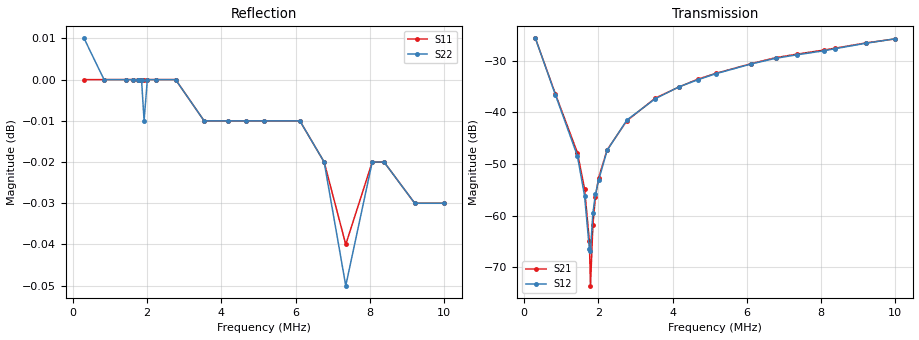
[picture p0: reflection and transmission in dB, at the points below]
!s-Parameter Generated by FASTRON Sdn. Bhd.
!FASTRON P/N : 1812AFTC-102X
!Keysight Technologies: E5071C_MY46733604_B.14.02
!Date: Wed Mar 18 13:59:20 2026
!Version  :Rev00  Wed Mar 18 13:59:20 2026
!Data & Calibration Information:
!Freq  S11:SOLT2(ON)  S21:SOLT2(ON)  S12:SOLT2(ON)  S22:SOLT2(ON)
!PortZ  Port1:50+j0  Port2:50+j0
!When reading reference impedance value at option line is always used.
! Remarks : This data is being provided solely for informational purposes.
# Hz S dB R 50
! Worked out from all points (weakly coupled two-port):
!   1601 points, 300 kHz to 10 MHz, reference 50 ohm
!   highest |S21| = -25.67 dB at 300 kHz (marker M1); lowest = -73.6 dB at 1.784 MHz (marker M2)
!   lowest |S11| = 0.0 dB at 7.353 MHz (marker M3), VSWR 465.81, Z = 0.15 - j31.6 ohm
!   |S11| at or under -10 dB: nowhere
!   |S22| runs from -0.1 to 0.0 dB; largest |S21 - S12| = 0.00091
!   S11 on the Smith chart (normalised r, x): 300 kHz: -0.01, +8.99; 2.232 MHz: 0.00, +1.31; 4.173 MHz: 0.00, +0.37; 6.115 MHz: 0.00, -0.21; 8.066 MHz: 0.00, -0.97; 10 MHz: 0.03, -4.09
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300000  0.00 12.7  -25.67 -85.6  -25.67 -85.4  0.01 -8.4
838135  -0.00 28.8  -36.43 -88.8  -36.60 -89.0  -0.00 -30.0
1431637  0.00 48.2  -47.83 -86.2  -48.45 -87.1  -0.00 -52.4
1624060  -0.00 54.5  -54.79 -76.8  -56.18 -79.9  -0.00 -59.5
1753659  -0.00 58.8  -64.90 -19.8  -66.40 -16.5  -0.00 -64.4
1784153  -0.00 59.8  -73.60 0.1  -66.81 28.7  -0.00 -65.5
1848952  -0.00 61.9  -61.83 59.9  -59.53 57.7  -0.00 -67.9
1917564  -0.00 64.2  -56.36 74.2  -55.87 77.1  -0.01 -70.5
2005233  -0.00 67.1  -52.64 77.1  -53.12 75.7  -0.00 -73.7
2231812  -0.00 74.5  -47.29 83.0  -47.39 83.9  -0.00 -82.1
2766665  -0.00 92.3  -41.62 81.1  -41.49 82.2  -0.00 -102.0
3534704  -0.01 117.8  -37.23 80.5  -37.35 81.2  -0.01 -130.4
4173488  -0.01 139.0  -35.08 80.4  -35.05 80.3  -0.01 -154.1
4669598  -0.01 155.5  -33.60 79.6  -33.72 79.7  -0.01 -172.4
5155786  -0.01 171.6  -32.47 78.9  -32.53 78.6  -0.01 169.6
6115250  -0.01 -156.5  -30.57 76.5  -30.63 76.9  -0.01 134.0
6770355  -0.02 -134.8  -29.42 75.0  -29.54 75.1  -0.02 109.8
7352716  -0.04 -115.4  -28.72 71.8  -28.85 71.9  -0.05 88.3
8066168  -0.02 -91.6  -27.95 72.4  -28.09 72.4  -0.02 62.0
8385344  -0.02 -81.1  -27.56 71.9  -27.66 71.9  -0.02 50.1
9211447  -0.03 -53.6  -26.55 70.4  -26.61 70.4  -0.03 19.5
1e7  -0.03 -27.5  -25.77 68.7  -25.75 68.8  -0.03 -9.7
